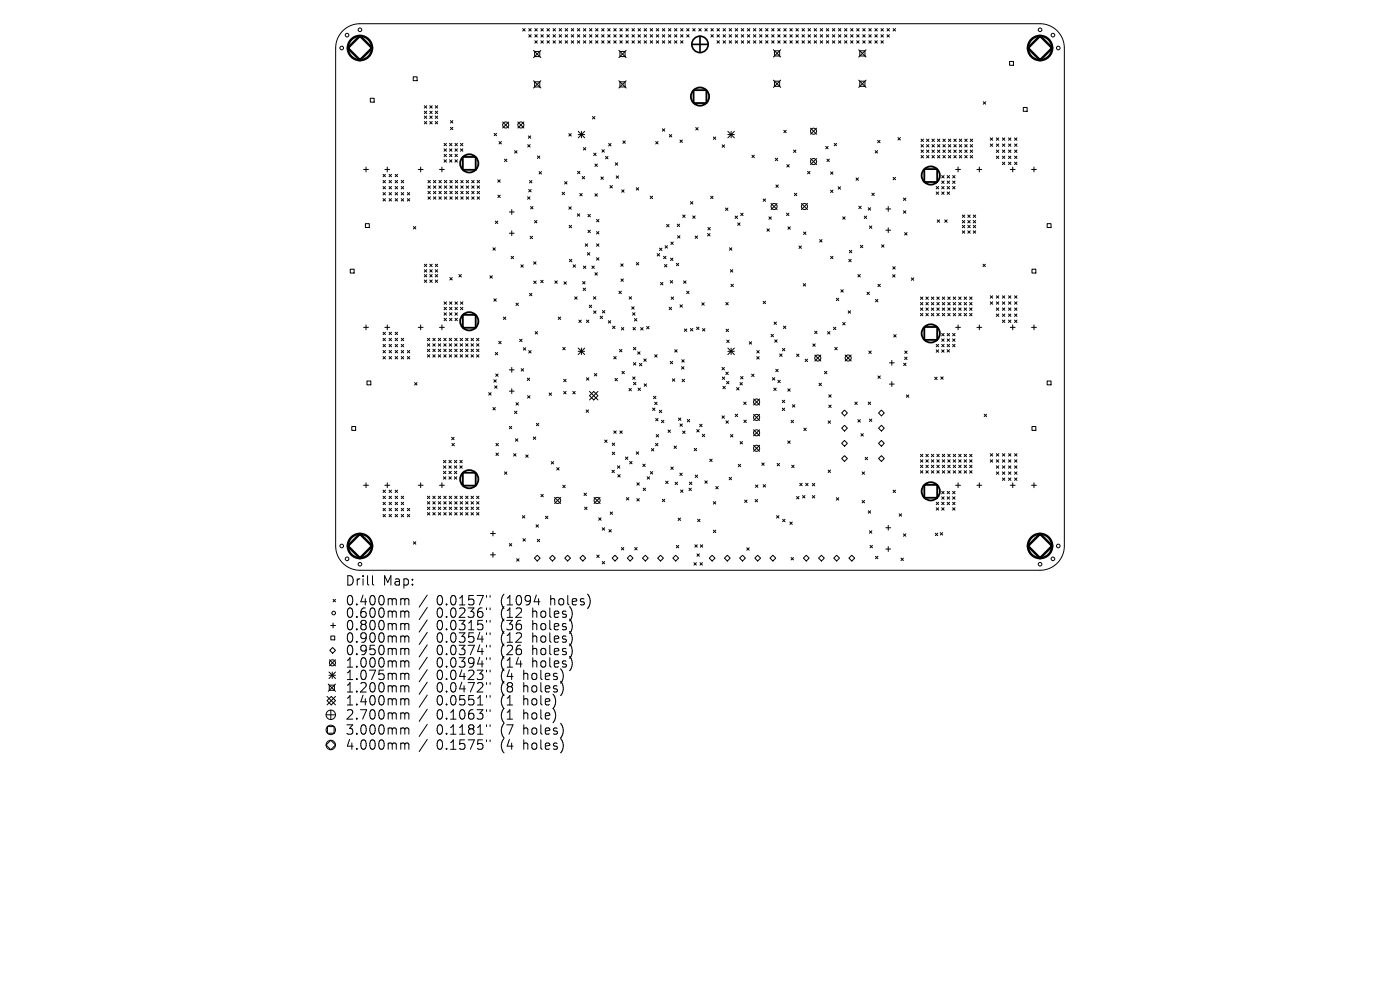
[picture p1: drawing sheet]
<svg xmlns="http://www.w3.org/2000/svg" width="297mm" height="210mm" viewBox="0 0 297 210" stroke-linecap="round" stroke-linejoin="round" font-family="sans-serif">
<defs><g id="words">
<g font-size="2.8">
<text x="73.2" y="124.5">Drill</text>
<text x="81.2" y="124.5">Map:</text>
<text x="73.2" y="128.7">0.400mm</text>
<text x="73.2" y="131.3">0.600mm</text>
<text x="92.6" y="128.7">0.0157&quot;</text>
<text x="92.6" y="131.3">0.0236&quot;</text>
<text x="106.3" y="128.7">(1094</text>
<text x="106.3" y="131.3">(12</text>
<text x="113.2" y="131.3">holes)</text>
<text x="117" y="128.7">holes)</text>
<text x="73.2" y="134">0.800mm</text>
<text x="73.2" y="136.6">0.900mm</text>
<text x="92.6" y="134">0.0315&quot;</text>
<text x="92.6" y="136.6">0.0354&quot;</text>
<text x="106.3" y="134">(36</text>
<text x="106.3" y="136.6">(12</text>
<text x="113.2" y="134">holes)</text>
<text x="113.2" y="136.6">holes)</text>
<text x="73.2" y="139.3">0.950mm</text>
<text x="73.2" y="141.9">1.000mm</text>
<text x="92.6" y="139.3">0.0374&quot;</text>
<text x="92.6" y="141.9">0.0394&quot;</text>
<text x="106.3" y="139.3">(26</text>
<text x="106.3" y="141.9">(14</text>
<text x="113.2" y="139.3">holes)</text>
<text x="113.2" y="141.9">holes)</text>
<text x="73.2" y="144.5">1.075mm</text>
<text x="73.2" y="147.2">1.200mm</text>
<text x="73.2" y="149.9">1.400mm</text>
<text x="92.6" y="144.5">0.0423&quot;</text>
<text x="92.6" y="147.2">0.0472&quot;</text>
<text x="92.6" y="149.9">0.0551&quot;</text>
<text x="106.3" y="144.5">(4</text>
<text x="106.3" y="147.2">(8</text>
<text x="106.3" y="149.9">(1</text>
<text x="111.3" y="144.5">holes)</text>
<text x="111.3" y="147.2">holes)</text>
<text x="111.3" y="149.9">hole)</text>
<text x="73.2" y="152.9">2.700mm</text>
<text x="92.6" y="152.9">0.1063&quot;</text>
<text x="106.3" y="152.9">(1</text>
<text x="111.3" y="152.9">hole)</text>
<text x="73.2" y="156.1">3.000mm</text>
<text x="73.2" y="159.3">4.000mm</text>
<text x="92.6" y="156.1">0.1181&quot;</text>
<text x="92.6" y="159.3">0.1575&quot;</text>
<text x="106.3" y="156.1">(7</text>
<text x="106.3" y="159.3">(4</text>
<text x="111.3" y="156.1">holes)</text>
<text x="111.3" y="159.3">holes)</text>
</g>
</g></defs>
<g fill="none" stroke="#000" stroke-width=".21">
<path d="M72.7 6.5a5.2 5.2 0 0 1 3.7-1.5h144.2a5.2 5.2 0 0 1 5.2 5.2v105.6a5.2 5.2 0 0 1-5.2 5.2h-144.2a5.2 5.2 0 0 1-5.2-5.2v-105.6a5.2 5.2 0 0 1 1.5-3.7zM87.7 16.3h.8v.8h-.8zM110.9 6.1l.5 .5M111.4 6.1l-.5 .5M112.2 7.4l.5 .5M112.2 6.1l.5 .5M112.7 7.4l-.5 .5M112.7 6.1l-.5 .5M113.2 17.1l1.5 1.6M113.2 10.7l1.5 1.5M113.4 10.9h1.1v1.1h-1.1zM113.4 17.4h1.1v1h-1.1z"/>
<path d="M113.5 8.6l.5 .6M113.5 6.1l.5 .5M113.5 7.4l.5 .5M114 6.1l-.5 .5M114 7.4l-.5 .5M114 8.6l-.5 .6M114.7 10.7l-1.5 1.5M114.7 17.1l-1.5 1.6M114.7 7.4l.6 .5M114.7 8.6l.6 .6M114.7 6.1l.6 .5M115.3 6.1l-.6 .5"/>
<path d="M115.3 7.4l-.6 .5M115.3 8.6l-.6 .6M116 8.6l.6 .6M116 7.4l.6 .5M116 6.1l.6 .5M116.6 6.1l-.6 .5M116.6 7.4l-.6 .5M116.6 8.6l-.6 .6M117.3 8.6l.5 .6M117.3 7.4l.5 .5M117.3 6.1l.5 .5M117.8 6.1l-.5 .5"/>
<path d="M117.8 7.4l-.5 .5M117.8 8.6l-.5 .6M118.6 8.6l.5 .6M118.6 7.4l.5 .5M118.6 6.1l.5 .5M119.1 6.1l-.5 .5M119.1 8.6l-.5 .6M119.1 7.4l-.5 .5M119.9 8.6l.5 .6M119.9 7.4l.5 .5M119.9 6.1l.5 .5M120.4 7.4l-.5 .5"/>
<path d="M120.4 8.6l-.5 .6M120.4 6.1l-.5 .5M121.2 8.6l.5 .6M121.2 7.4l.5 .5M121.2 6.1l.5 .5M121.7 6.1l-.5 .5M121.7 7.4l-.5 .5M121.7 8.6l-.5 .6M122.5 8.6l.5 .6M122.5 7.4l.5 .5M122.5 6.1l.5 .5M123 6.1l-.5 .5"/>
<path d="M123 7.4l-.5 .5M123 8.6l-.5 .6M123.8 7.4l.5 .5M123.8 6.1l.5 .5M123.8 8.6l.5 .6M124.3 6.1l-.5 .5M124.3 7.4l-.5 .5M124.3 8.6l-.5 .6M125.1 8.6l.5 .6M125.1 7.4l.5 .5M125.1 6.1l.5 .5M125.6 8.6l-.5 .6"/>
<path d="M125.6 6.1l-.5 .5M125.6 7.4l-.5 .5M126.3 8.6l.6 .6M126.3 7.4l.6 .5M126.3 6.1l.6 .5M126.9 7.4l-.6 .5M126.9 6.1l-.6 .5M126.9 8.6l-.6 .6M127.6 8.6l.5 .6M127.6 7.4l.5 .5M127.6 6.1l.5 .5M128.1 6.1l-.5 .5"/>
<path d="M128.1 7.4l-.5 .5M128.1 8.6l-.5 .6M128.9 8.6l.5 .6M128.9 7.4l.5 .5M128.9 6.1l.5 .5M129.4 6.1l-.5 .5M129.4 7.4l-.5 .5M129.4 8.6l-.5 .6M130.2 8.6l.5 .6M130.2 7.4l.5 .5M130.2 6.1l.5 .5M130.7 6.1l-.5 .5"/>
<path d="M130.7 7.4l-.5 .5M130.7 8.6l-.5 .6M131.3 10.7l1.5 1.5M131.3 17.1l1.5 1.6M131.5 8.6l.5 .6M131.5 7.4l.5 .5M131.5 6.1l.5 .5M131.5 10.9h1.1v1.1h-1.1zM131.5 17.4h1.1v1h-1.1zM132 6.1l-.5 .5M132 7.4l-.5 .5M132 8.6l-.5 .6"/>
<path d="M132.8 8.6l.5 .6M132.8 7.4l.5 .5M132.8 6.1l.5 .5M132.8 10.7l-1.5 1.5M132.8 17.1l-1.5 1.6M133.3 6.1l-.5 .5M133.3 7.4l-.5 .5M133.3 8.6l-.5 .6M134.1 8.6l.5 .6M134.1 7.4l.5 .5M134.1 6.1l.5 .5M134.6 6.1l-.5 .5"/>
<path d="M134.6 7.4l-.5 .5M134.6 8.6l-.5 .6M135.4 8.6l.5 .6M135.4 7.4l.5 .5M135.4 6.1l.5 .5M135.9 6.1l-.5 .5M135.9 7.4l-.5 .5M135.9 8.6l-.5 .6M136.6 8.6l.6 .6M136.6 7.4l.6 .5M136.6 6.1l.6 .5M137.2 6.1l-.6 .5"/>
<path d="M137.2 7.4l-.6 .5M137.2 8.6l-.6 .6M137.9 8.6l.6 .6M137.9 7.4l.6 .5M137.9 6.1l.6 .5M138.5 6.1l-.6 .5M138.5 7.4l-.6 .5M138.5 8.6l-.6 .6M139.2 8.6l.5 .6M139.2 6.1l.5 .5M139.2 7.4l.5 .5M139.7 6.1l-.5 .5"/>
<path d="M139.7 7.4l-.5 .5M139.7 8.6l-.5 .6M140.5 7.4l.5 .5M140.5 8.6l.5 .6M140.5 6.1l.5 .5M141 6.1l-.5 .5M141 7.4l-.5 .5M141 8.6l-.5 .6M141.8 8.6l.5 .6M141.8 7.4l.5 .5M141.8 6.1l.5 .5M142.3 6.1l-.5 .5"/>
<path d="M142.3 7.4l-.5 .5M142.3 8.6l-.5 .6M143.1 8.6l.5 .6M143.1 7.4l.5 .5M143.1 6.1l.5 .5M143.6 8.6l-.5 .6M143.6 6.1l-.5 .5M143.6 7.4l-.5 .5M144.4 8.6l.5 .6M144.4 7.4l.5 .5M144.4 6.1l.5 .5M144.9 7.4l-.5 .5"/>
<path d="M144.9 8.6l-.5 .6M144.9 6.1l-.5 .5M145.7 7.4l.5 .5M145.7 6.1l.5 .5M146.2 6.1l-.5 .5M146.2 7.4l-.5 .5M147 6.1l.5 .5M147.5 6.1l-.5 .5M148.2 6.1l.6 .5M148.8 6.1l-.6 .5M149.5 6.1l.5 .5M150 6.1l-.5 .5"/>
<path d="M150.8 7.4l.5 .5M150.8 6.1l.5 .5M151.3 6.1l-.5 .5M151.3 7.4l-.5 .5M152.1 8.6l.5 .6M152.1 7.4l.5 .5M152.1 6.1l.5 .5M152.6 6.1l-.5 .5M152.6 7.4l-.5 .5M152.6 8.6l-.5 .6M153.4 8.6l.5 .6M153.4 7.4l.5 .5"/>
<path d="M153.4 6.1l.5 .5M153.9 6.1l-.5 .5M153.9 7.4l-.5 .5M153.9 8.6l-.5 .6M154.7 8.6l.5 .6M154.7 7.4l.5 .5M154.7 6.1l.5 .5M155.2 6.1l-.5 .5M155.2 7.4l-.5 .5M155.2 8.6l-.5 .6M156 8.6l.5 .6M156 7.4l.5 .5"/>
<path d="M156 6.1l.5 .5M156.5 6.1l-.5 .5M156.5 7.4l-.5 .5M156.5 8.6l-.5 .6M157.3 8.6l.5 .6M157.3 7.4l.5 .5M157.3 6.1l.5 .5M157.8 8.6l-.5 .6M157.8 6.1l-.5 .5M157.8 7.4l-.5 .5M158.5 8.6l.6 .6M158.5 7.4l.6 .5"/>
<path d="M158.5 6.1l.6 .5M159.1 7.4l-.6 .5M159.1 6.1l-.6 .5M159.1 8.6l-.6 .6M159.8 8.6l.6 .6M159.8 7.4l.6 .5M159.8 6.1l.6 .5M160.4 6.1l-.6 .5M160.4 7.4l-.6 .5M160.4 8.6l-.6 .6M161.1 8.6l.5 .6M161.1 7.4l.5 .5"/>
<path d="M161.1 6.1l.5 .5M161.6 6.1l-.5 .5M161.6 7.4l-.5 .5M161.6 8.6l-.5 .6M162.4 8.6l.5 .6M162.4 7.4l.5 .5M162.4 6.1l.5 .5M162.9 6.1l-.5 .5M162.9 7.4l-.5 .5M162.9 8.6l-.5 .6M163.7 8.6l.5 .6M163.7 7.4l.5 .5"/>
<path d="M163.7 6.1l.5 .5M164.1 10.6l1.5 1.5M164.1 17l1.5 1.5M164.2 6.1l-.5 .5M164.2 7.4l-.5 .5M164.2 8.6l-.5 .6M164.3 10.8h1.1v1.1h-1.1zM164.3 17.2h1.1v1.1h-1.1zM165 8.6l.5 .6M165 7.4l.5 .5M165 6.1l.5 .5M165.5 6.1l-.5 .5"/>
<path d="M165.5 7.4l-.5 .5M165.5 8.6l-.5 .6M165.6 10.6l-1.5 1.5M165.6 17l-1.5 1.5M166.3 7.4l.5 .5M166.3 6.1l.5 .5M166.3 8.6l.5 .6M166.8 6.1l-.5 .5M166.8 7.4l-.5 .5M166.8 8.6l-.5 .6M167.6 8.6l.5 .6M167.6 7.4l.5 .5"/>
<path d="M167.6 6.1l.5 .5M168.1 6.1l-.5 .5M168.1 7.4l-.5 .5M168.1 8.6l-.5 .6M168.9 8.6l.5 .6M168.9 7.4l.5 .5M168.9 6.1l.5 .5M169.4 6.1l-.5 .5M169.4 7.4l-.5 .5M169.4 8.6l-.5 .6M170.1 8.6l.6 .6M170.1 7.4l.6 .5"/>
<path d="M170.1 6.1l.6 .5M170.7 6.1l-.6 .5M170.7 7.4l-.6 .5M170.7 8.6l-.6 .6M171.4 8.6l.5 .6M171.4 7.4l.5 .5M171.4 6.1l.5 .5M171.9 6.1l-.5 .5M171.9 7.4l-.5 .5M171.9 8.6l-.5 .6M172.7 8.6l.5 .6M172.7 7.4l.5 .5"/>
<path d="M172.7 6.1l.5 .5M173.2 6.1l-.5 .5M173.2 7.4l-.5 .5M173.2 8.6l-.5 .6M174 8.6l.5 .6M174 7.4l.5 .5M174 6.1l.5 .5M174.5 6.1l-.5 .5M174.5 7.4l-.5 .5M174.5 8.6l-.5 .6M175.3 8.6l.5 .6M175.3 7.4l.5 .5"/>
<path d="M175.3 6.1l.5 .5M175.8 8.6l-.5 .6M175.8 6.1l-.5 .5M175.8 7.4l-.5 .5M176.6 8.6l.5 .6M176.6 7.4l.5 .5M176.6 6.1l.5 .5M177.1 7.4l-.5 .5M177.1 6.1l-.5 .5M177.1 8.6l-.5 .6M177.9 8.6l.5 .6M177.9 7.4l.5 .5"/>
<path d="M177.9 6.1l.5 .5M178.4 8.6l-.5 .6M178.4 6.1l-.5 .5M178.4 7.4l-.5 .5M179.2 8.6l.5 .6M179.2 7.4l.5 .5M179.2 6.1l.5 .5M179.7 8.6l-.5 .6M179.7 7.4l-.5 .5M179.7 6.1l-.5 .5M180.4 8.6l.6 .6M180.4 7.4l.6 .5"/>
<path d="M180.4 6.1l.6 .5M181 7.4l-.6 .5M181 8.6l-.6 .6M181 6.1l-.6 .5M181.7 8.6l.6 .6M181.7 6.1l.6 .5M181.7 7.4l.6 .5M182.2 10.6l1.5 1.5M182.2 17l1.5 1.5M182.3 6.1l-.6 .5M182.3 7.4l-.6 .5M182.3 8.6l-.6 .6"/>
<path d="M182.4 10.8h1.1v1.1h-1.1zM182.4 17.2h1.1v1.1h-1.1zM183 7.4l.5 .5M183 8.6l.5 .6M183 6.1l.5 .5M183.5 6.1l-.5 .5M183.5 8.6l-.5 .6M183.5 7.4l-.5 .5M183.7 10.6l-1.5 1.5M183.7 17l-1.5 1.5M184.3 8.6l.5 .6M184.3 7.4l.5 .5"/>
<path d="M184.3 6.1l.5 .5M184.8 7.4l-.5 .5M184.8 6.1l-.5 .5M184.8 8.6l-.5 .6M185.6 8.6l.5 .6M185.6 7.4l.5 .5M185.6 6.1l.5 .5M186.1 8.6l-.5 .6M186.1 6.1l-.5 .5M186.1 7.4l-.5 .5M186.9 8.6l.5 .6M186.9 7.4l.5 .5"/>
<path d="M186.9 6.1l.5 .5M187.4 7.4l-.5 .5M187.4 8.6l-.5 .6M187.4 6.1l-.5 .5M188.2 7.4l.5 .5M188.2 6.1l.5 .5M188.7 6.1l-.5 .5M188.7 7.4l-.5 .5M189.5 6.1l.5 .5M190 6.1l-.5 .5M214.2 13h.8v.9h-.8zM77.1 35.9h1.1"/>
<path d="M77.6 35.4v1.1M78.6 20.8h.8v.9h-.8zM81.3 37l.5 .5M81.3 38.3l.5 .5M81.3 39.6l.5 .5M81.6 35.9h1.1M81.8 37l-.5 .5M81.8 38.3l-.5 .5M81.8 39.6l-.5 .5M82.2 35.4v1.1M82.5 38.3l.6 .5M82.5 39.6l.6 .5"/>
<path d="M82.5 37l.6 .5M83.1 37l-.6 .5M83.1 38.3l-.6 .5M83.1 39.6l-.6 .5M83.8 39.6l.5 .5M83.8 38.3l.5 .5M83.8 37l.5 .5M84.3 37l-.5 .5M84.3 38.3l-.5 .5M84.3 39.6l-.5 .5M85.1 39.6l.5 .5M85.1 38.3l.5 .5"/>
<path d="M85.6 38.3l-.5 .5M85.6 39.6l-.5 .5M88.7 35.9h1.1M89.2 35.4v1.1M90 22.4l.5 .5M90 23.6l.5 .5M90 24.6l.5 .5M90 25.8l.5 .5M90.5 22.4l-.5 .5M90.5 23.6l-.5 .5M90.5 24.6l-.5 .5M90.5 25.8l-.5 .5"/>
<path d="M90.8 38.3l.5 .5M90.8 39.4l.5 .5M91.2 23.6l.5 .5M91.2 25.8l.5 .5M91.2 22.4l.5 .5M91.2 24.6l.5 .5M91.3 38.3l-.5 .5M91.3 39.4l-.5 .5M91.7 22.4l-.5 .5M91.7 24.6l-.5 .5M91.7 23.6l-.5 .5M91.7 25.8l-.5 .5"/>
<path d="M91.9 39.4l.6 .5M91.9 38.3l.6 .5M92.3 25.8l.5 .5M92.3 22.4l.5 .5M92.3 23.6l.5 .5M92.3 24.6l.5 .5M92.5 38.3l-.6 .5M92.5 39.4l-.6 .5M92.8 22.4l-.5 .5M92.8 24.6l-.5 .5M92.8 23.6l-.5 .5M92.8 25.8l-.5 .5"/>
<path d="M93.1 39.4l.5 .5M93.1 38.3l.5 .5M93.2 35.9h1.1M93.6 38.3l-.5 .5M93.6 39.4l-.5 .5M93.8 35.4v1.1M94.2 30.4l.5 .5M94.2 31.6l.5 .5M94.2 32.7l.5 .5M94.2 33.9l.5 .5M94.3 39.4l.5 .5M94.3 38.3l.5 .5"/>
<path d="M94.7 30.4l-.5 .5M94.7 31.6l-.5 .5M94.7 32.7l-.5 .5M94.7 33.9l-.5 .5M94.8 38.3l-.5 .5M94.8 39.4l-.5 .5M95.4 31.6l.5 .5M95.4 32.7l.5 .5M95.4 33.9l.5 .5M95.4 30.4l.5 .5M95.4 39.4l.5 .5M95.4 38.3l.5 .5"/>
<path d="M95.6 25.6l.5 .5M95.6 27l.5 .5M95.9 30.4l-.5 .5M95.9 31.6l-.5 .5M95.9 32.7l-.5 .5M95.9 33.9l-.5 .5M95.9 39.4l-.5 .5M95.9 38.3l-.5 .5M96.1 25.6l-.5 .5M96.1 27l-.5 .5M96.5 32.7l.5 .5M96.5 33.9l.5 .5"/>
<path d="M96.5 31.6l.5 .5M96.5 30.4l.5 .5M96.6 39.4l.5 .5M96.6 38.3l.5 .5M97 30.4l-.5 .5M97 31.6l-.5 .5M97 32.7l-.5 .5M97 33.9l-.5 .5M97.1 38.3l-.5 .5M97.1 39.4l-.5 .5M97.7 31.6l.5 .5M97.7 30.4l.5 .5"/>
<path d="M97.7 39.4l.6 .5M97.7 38.3l.6 .5M98.2 30.4l-.5 .5M98.2 31.6l-.5 .5M98.3 38.3l-.6 .5M98.3 39.4l-.6 .5M98.9 39.4l.5 .5M98.9 38.3l.5 .5M99.4 38.3l-.5 .5M99.4 39.4l-.5 .5M100.1 39.4l.5 .5M100.1 38.3l.5 .5"/>
<path d="M100.6 38.3l-.5 .5M100.6 39.4l-.5 .5M101.2 39.4l.5 .5M101.2 38.3l.5 .5M101.7 38.3l-.5 .5M101.7 39.4l-.5 .5M104.8 28.3l.5 .5M105.3 28.3l-.5 .5M105.6 38.1l.5 .6M105.9 30l.5 .5M106.1 38.1l-.5 .6M106.4 30l-.5 .5"/>
<path d="M106.6 25.9l1.3 1.3M107 33.8l.5 .5M107.5 33.8l-.5 .5M107.9 25.9l-1.3 1.3M109.2 32l.5 .5M109.7 32l-.5 .5M109.9 25.9l1.2 1.3M111.1 25.9l-1.2 1.3M111.9 30.7l.6 .5M112.1 28.8l.5 .5M112.3 38.3l.5 .5M112.5 30.7l-.6 .5"/>
<path d="M112.6 28.8l-.5 .5M112.8 38.3l-.5 .5M114 33.1l.5 .5M114.4 36.4l.5 .5M114.5 33.1l-.5 .5M114.9 36.4l-.5 .5M119.8 38.5l.5 .5M120.3 38.5l-.5 .5M120.7 28.3l.5 .6M121.2 28.3l-.5 .6M122.5 36.3l.5 .6M122.7 27.9l1.3 1.3"/>
<path d="M122.7 28.5h1.3M123 36.3l-.5 .6M123.3 27.9v1.3M123.5 37.4l.5 .5M123.8 31.3l.5 .5M124 37.4l-.5 .5M124 27.9l-1.3 1.3M124.3 31.3l-.5 .5M125.7 24.7l.5 .5M125.9 32.5l.6 .5M126.2 24.7l-.5 .5M126.2 34.8l.5 .5"/>
<path d="M126.5 32.5l-.6 .5M126.7 34.8l-.5 .5M127.5 37.5l.5 .6M127.7 31.8l.5 .5M128 37.5l-.5 .6M128.2 31.8l-.5 .5M128.5 33.2l.5 .5M129 33.2l-.5 .5M129.1 30.4l.5 .6M129.4 39.4l.5 .5M129.6 30.4l-.5 .6M129.9 39.4l-.5 .5"/>
<path d="M130.5 34.5l.5 .5M130.7 37.3l.5 .5M131 34.5l-.5 .5M131.2 37.3l-.5 .5M132.1 29.9l.6 .5M132.7 29.9l-.6 .5M135 39.8l.5 .5M135.5 39.8l-.5 .5M139.1 30l.5 .5M139.6 30l-.5 .5M140.5 27.3l.5 .5M141 27.3l-.5 .5"/>
<path d="M142 28.5l.5 .6M142.5 28.5l-.5 .6M144.2 29.7l.6 .5M144.8 29.7l-.6 .5M147.6 27.1l.5 .5M148.1 27.1l-.5 .5M151.3 29.1l.6 .5M151.9 29.1l-.6 .5M153.2 30.7l.5 .5M153.7 30.7l-.5 .5M154.4 27.9l1.4 1.3M154.4 28.5h1.4"/>
<path d="M155.1 27.9v1.3M155.8 27.9l-1.4 1.3M159.5 32.9l.5 .5M160 32.9l-.5 .5M164.5 33.6l.5 .5M164.6 39.2l.5 .5M165 33.6l-.5 .5M165.1 39.2l-.5 .5M166.3 27.6l.5 .6M166.8 27.6l-.5 .6M166.9 34.9l.5 .5M167.4 34.9l-.5 .5"/>
<path d="M168.3 31.8l.6 .5M168.9 31.8l-.6 .5M171.3 36.4l.5 .5M171.8 36.4l-.5 .5M171.9 27.2l1.3 1.3M171.9 33.6l1.3 1.3M173.2 33.6l-1.3 1.3M173.2 27.2l-1.3 1.3M175.2 31.1l.5 .5M175.4 33.8l.5 .5M175.7 31.1l-.5 .5M175.9 33.8l-.5 .5"/>
<path d="M176.2 36.5l.5 .5M176.7 36.5l-.5 .5M177 30.4l.5 .5M177.5 30.4l-.5 .5M177.8 39.6l.5 .5M178.3 39.6l-.5 .5M181.6 37.7l.5 .6M182.1 37.7l-.5 .6M185.7 32l.5 .5M186.2 32l-.5 .5M186.2 29.8l.5 .5M186.7 29.8l-.5 .5"/>
<path d="M189.5 37.6l.5 .5M190 37.6l-.5 .5M190.5 29.2l.5 .5M191 29.2l-.5 .5M195.4 29.5l.5 .5M195.4 30.7l.5 .5M195.4 31.8l.5 .5M195.4 33l.5 .5M195.9 33l-.5 .5M195.9 29.5l-.5 .5M195.9 30.7l-.5 .5M195.9 31.8l-.5 .5"/>
<path d="M196.6 30.7l.5 .5M196.6 31.8l.5 .5M196.6 33l.5 .5M196.6 29.5l.5 .5M197.1 31.8l-.5 .5M197.1 33l-.5 .5M197.1 29.5l-.5 .5M197.1 30.7l-.5 .5M197.7 31.8l.5 .5M197.7 33l.5 .5M197.7 30.7l.5 .5M197.7 29.5l.5 .5"/>
<path d="M198.2 30.7l-.5 .5M198.2 31.8l-.5 .5M198.2 29.5l-.5 .5M198.2 33l-.5 .5M198.6 39.6l.5 .5M198.9 33l.5 .5M198.9 31.8l.5 .5M198.9 30.7l.5 .5M198.9 29.5l.5 .5M199.1 39.6l-.5 .5M199.4 29.5l-.5 .5M199.4 30.7l-.5 .5"/>
<path d="M199.4 31.8l-.5 .5M199.4 33l-.5 .5M199.8 38.4l.5 .5M199.8 37.2l.5 .6M199.8 39.6l.5 .5M200 33l.5 .5M200 31.8l.5 .5M200 30.7l.5 .5M200 29.5l.5 .5M200.3 37.2l-.5 .6M200.3 38.4l-.5 .5M200.3 39.6l-.5 .5"/>
<path d="M200.5 29.5l-.5 .5M200.5 30.7l-.5 .5M200.5 31.8l-.5 .5M200.5 33l-.5 .5M200.9 39.6l.5 .5M200.9 38.4l.5 .5M200.9 37.2l.5 .6M201.2 33l.5 .5M201.2 31.8l.5 .5M201.2 30.7l.5 .5M201.2 29.5l.5 .5M201.4 37.2l-.5 .6"/>
<path d="M201.4 38.4l-.5 .5M201.4 39.6l-.5 .5M201.7 33l-.5 .5M201.7 29.5l-.5 .5M201.7 30.7l-.5 .5M201.7 31.8l-.5 .5M202.1 38.4l.5 .5M202.1 37.2l.5 .6M202.1 39.6l.5 .5M202.3 33l.6 .5M202.3 31.8l.6 .5M202.3 30.7l.6 .5"/>
<path d="M202.3 29.5l.6 .5M202.6 37.2l-.5 .6M202.6 38.4l-.5 .5M202.6 39.6l-.5 .5M202.7 35.9h1.1M202.9 31.8l-.6 .5M202.9 33l-.6 .5M202.9 29.5l-.6 .5M202.9 30.7l-.6 .5M203.3 35.4v1.1M203.5 33l.5 .5M203.5 31.8l.5 .5"/>
<path d="M203.5 30.7l.5 .5M203.5 29.5l.5 .5M204 30.7l-.5 .5M204 31.8l-.5 .5M204 29.5l-.5 .5M204 33l-.5 .5M204.7 33l.5 .5M204.7 31.8l.5 .5M204.7 29.5l.5 .5M204.7 30.7l.5 .5M205.2 29.5l-.5 .5M205.2 30.7l-.5 .5"/>
<path d="M205.2 31.8l-.5 .5M205.2 33l-.5 .5M205.8 33l.5 .5M205.8 30.7l.5 .5M205.8 31.8l.5 .5M205.8 29.5l.5 .5M206.3 33l-.5 .5M206.3 29.5l-.5 .5M206.3 30.7l-.5 .5M206.3 31.8l-.5 .5M207.2 35.9h1.1M207.8 35.4v1.1"/>
<path d="M208.6 21.6l.5 .5M209.1 21.6l-.5 .5M210.1 29.3l.5 .5M210.1 30.5l.5 .6M210.6 29.3l-.5 .5M210.6 30.5l-.5 .6M211.4 29.3l.5 .5M211.4 30.5l.5 .6M211.4 31.8l.5 .5M211.4 33.1l.5 .5M211.9 29.3l-.5 .5M211.9 30.5l-.5 .6"/>
<path d="M211.9 31.8l-.5 .5M211.9 33.1l-.5 .5M212.7 30.5l.5 .6M212.7 31.8l.5 .5M212.7 33.1l.5 .5M212.7 34.4l.5 .5M212.7 29.3l.5 .5M213.2 34.4l-.5 .5M213.2 29.3l-.5 .5M213.2 30.5l-.5 .6M213.2 31.8l-.5 .5M213.2 33.1l-.5 .5"/>
<path d="M213.9 33.1l.6 .5M213.9 34.4l.6 .5M213.9 30.5l.6 .6M213.9 29.3l.6 .5M213.9 31.8l.6 .5M214.3 35.9h1.1M214.5 34.4l-.6 .5M214.5 33.1l-.6 .5M214.5 29.3l-.6 .5M214.5 30.5l-.6 .6M214.5 31.8l-.6 .5M214.8 35.4v1.1"/>
<path d="M215.2 34.4l.5 .5M215.2 31.8l.5 .5M215.2 30.5l.5 .6M215.2 33.1l.5 .5M215.2 29.3l.5 .5M215.7 33.1l-.5 .5M215.7 34.4l-.5 .5M215.7 31.8l-.5 .5M215.7 29.3l-.5 .5M215.7 30.5l-.5 .6M217.1 22.8h.8v.8h-.8zM218.8 35.9h1.1"/>
<path d="M219.4 35.4v1.1M74.3 57.1h.8v.8h-.8zM77.5 47.4h.8v.9h-.8zM81.3 40.8l.5 .6M81.3 42.1l.5 .5M81.8 40.8l-.5 .6M81.8 42.1l-.5 .5M82.5 40.8l.6 .6M82.5 42.1l.6 .5M83.1 40.8l-.6 .6M83.1 42.1l-.6 .5M83.8 40.8l.5 .6"/>
<path d="M83.8 42.1l.5 .5M84.3 40.8l-.5 .6M84.3 42.1l-.5 .5M85.1 40.8l.5 .6M85.1 42.1l.5 .5M85.6 40.8l-.5 .6M85.6 42.1l-.5 .5M86.4 42.1l.5 .5M86.4 40.8l.5 .6M86.9 40.8l-.5 .6M86.9 42.1l-.5 .5M87.7 48.1l.5 .5"/>
<path d="M88.2 48.1l-.5 .5M90 56l.5 .6M90 57.2l.5 .5M90 58.2l.5 .6M90 59.4l.5 .5M90.5 56l-.5 .6M90.5 57.2l-.5 .5M90.5 58.2l-.5 .6M90.5 59.4l-.5 .5M90.8 40.6l.5 .5M90.8 41.7l.5 .6M91.2 57.2l.5 .5"/>
<path d="M91.2 59.4l.5 .5M91.2 56l.5 .6M91.2 58.2l.5 .6M91.3 40.6l-.5 .5M91.3 41.7l-.5 .6M91.7 56l-.5 .6M91.7 58.2l-.5 .6M91.7 57.2l-.5 .5M91.7 59.4l-.5 .5M91.9 40.6l.6 .5M91.9 41.7l.6 .6M92.3 57.2l.5 .5"/>
<path d="M92.3 59.4l.5 .5M92.3 56l.5 .6M92.3 58.2l.5 .6M92.5 40.6l-.6 .5M92.5 41.7l-.6 .6M92.8 59.4l-.5 .5M92.8 56l-.5 .6M92.8 58.2l-.5 .6M92.8 57.2l-.5 .5M93.1 40.6l.5 .5M93.1 41.7l.5 .6M93.6 40.6l-.5 .5"/>
<path d="M93.6 41.7l-.5 .6M94.3 41.7l.5 .6M94.3 40.6l.5 .5M94.8 40.6l-.5 .5M94.8 41.7l-.5 .6M95.4 41.7l.5 .6M95.4 40.6l.5 .5M95.4 58.9l.5 .5M95.9 58.9l-.5 .5M95.9 40.6l-.5 .5M95.9 41.7l-.5 .6M96.6 41.7l.5 .6"/>
<path d="M96.6 40.6l.5 .5M97.1 40.6l-.5 .5M97.1 41.7l-.5 .6M97.4 58.2l.5 .6M97.7 41.7l.6 .6M97.7 40.6l.6 .5M97.9 58.2l-.5 .6M98.3 40.6l-.6 .5M98.3 41.7l-.6 .6M98.9 40.6l.5 .5M98.9 41.7l.5 .6M99.4 40.6l-.5 .5"/>
<path d="M99.4 41.7l-.5 .6M100.1 41.7l.5 .6M100.1 40.6l.5 .5M100.6 40.6l-.5 .5M100.6 41.7l-.5 .6M101.2 41.7l.5 .6M101.2 40.6l.5 .5M101.7 40.6l-.5 .5M101.7 41.7l-.5 .6M103.9 58.5l.5 .5M104.4 58.5l-.5 .5M104.6 52.6l.5 .5"/>
<path d="M105.1 52.6l-.5 .5M105.1 46.9l.5 .5M105.6 46.9l-.5 .5M105.6 41.4l.5 .5M106.1 41.4l-.5 .5M108.1 45h1M108.1 49.5h1M108.4 54.4l.6 .5M108.6 44.5v1M108.6 49v1M109 54.4l-.6 .5M110.5 56.2l.5 .5"/>
<path d="M111 56.2l-.5 .5M111.9 41.7l.5 .6M112.2 40.2l.5 .5M112.4 41.7l-.5 .6M112.5 50.1l.5 .5M112.6 43.8l.5 .5M112.7 40.2l-.5 .5M113 50.1l-.5 .5M113.1 43.8l-.5 .5M113.2 55.5l.5 .5M113.2 59.6l.5 .5M113.4 46.8l.5 .5"/>
<path d="M113.7 55.5l-.5 .5M113.7 59.6l-.5 .5M113.9 46.8l-.5 .5M114.7 59.5l.5 .5M115.2 59.5l-.5 .5M117.7 59.6l.5 .5M118.2 59.6l-.5 .5M119.3 40.8l.5 .5M119.6 59.8l.6 .5M119.8 40.8l-.5 .5M120.2 59.8l-.6 .5M120.7 43.9l.5 .5"/>
<path d="M120.7 47.8l.6 .5M120.8 55l.5 .5M121.2 43.9l-.5 .5M121.3 47.8l-.6 .5M121.3 55l-.5 .5M121.6 56.2l.5 .5M122.1 56.2l-.5 .5M122.5 45.4l.5 .5M123 45.4l-.5 .5M123 41l.5 .6M123.5 41l-.5 .6M123.6 59.7l.5 .5"/>
<path d="M123.8 56.4l.5 .5M124.1 59.7l-.5 .5M124.2 51.7l.5 .5M124.3 56.4l-.5 .5M124.6 53.6l.5 .5M124.7 51.7l-.5 .5M124.7 48.8l.5 .5M124.7 45.5l.5 .5M125.1 53.6l-.5 .5M125.2 45.5l-.5 .5M125.2 48.8l-.5 .5M125.6 56.4l.5 .5"/>
<path d="M126.1 56.4l-.5 .5M126.2 41.1l.5 .5M126.2 57.8l.5 .6M126.5 46.6l.6 .5M126.5 49.1l.6 .5M126.5 51.7l.6 .5M126.5 54.7l.6 .5M126.7 41.1l-.5 .5M126.7 57.8l-.5 .6M127.1 46.6l-.6 .5M127.1 49.1l-.6 .5M127.1 51.7l-.6 .5"/>
<path d="M127.1 54.7l-.6 .5M131.7 56l.5 .5M131.7 59.2l.5 .5M131.9 40.3l.5 .5M132.2 56l-.5 .5M132.2 59.2l-.5 .5M132.4 40.3l-.5 .5M135 55.7l.5 .5M135.5 55.7l-.5 .5M137.9 41.6l.6 .5M138.5 41.6l-.6 .5M139.4 53.8l.5 .5"/>
<path d="M139.9 52.6l.5 .6M139.9 53.8l-.5 .5M140.1 59.9l.5 .5M140.4 52.6l-.5 .6M140.6 59.9l-.5 .5M140.8 54.4l.5 .5M141 56.1l.5 .5M141.1 52.1l.5 .5M141.3 54.4l-.5 .5M141.4 47.6l.5 .5M141.5 56.1l-.5 .5M141.6 52.1l-.5 .5"/>
<path d="M141.9 47.6l-.5 .5M142.2 59.5l.5 .5M142.3 54.8l.5 .5M142.3 51.3l.5 .6M142.7 59.5l-.5 .5M142.8 54.8l-.5 .5M142.8 51.3l-.5 .6M143.5 55.9l.5 .5M143.7 47.5l.5 .6M143.7 50l.5 .5M144 55.9l-.5 .5M144.2 47.5l-.5 .6"/>
<path d="M144.2 50l-.5 .5M144.8 45.6l.5 .5M145 59.6l.5 .5M145.3 45.6l-.5 .5M145.5 59.6l-.5 .5M146.5 42.8l.5 .5M147 45.8l.5 .5M147 42.8l-.5 .5M147.5 50.1l.5 .5M147.5 45.8l-.5 .5M148 50.1l-.5 .5M150.1 49.5l.5 .6"/>
<path d="M150.2 48.3l.5 .5M150.6 49.5l-.5 .6M150.7 48.3l-.5 .5M150.8 41.6l.5 .5M151.3 41.6l-.5 .5M153.9 44.1l.5 .5M154.4 44.1l-.5 .5M154.7 52.6l.6 .5M154.9 57.2l.6 .5M155.3 52.6l-.6 .5M155.5 57.2l-.6 .5M155.9 45.8l.6 .5"/>
<path d="M156.5 45.8l-.6 .5M156.5 47.3l.5 .5M157 47.3l-.5 .5M157.1 45.2l.5 .5M157.6 45.2l-.5 .5M161.9 42.2l.5 .5M162.4 42.2l-.5 .5M162.7 48.5l.5 .6M163.1 46l.5 .5M163.2 48.5l-.5 .6M163.6 43.2l1.3 1.3M163.6 46l-.5 .5"/>
<path d="M164.9 43.2l-1.3 1.3M166.9 45.2l.5 .5M167.1 48.1l.6 .5M167.4 45.2l-.5 .5M167.7 48.1l-.6 .5M168.5 41l.5 .5M169 41l-.5 .5M169.5 52.2l.5 .5M170 43.2l1.3 1.3M170 52.2l-.5 .5M170.5 49.2l.5 .5M171 49.2l-.5 .5"/>
<path d="M171.3 43.2l-1.3 1.3M173.9 50.8l.5 .5M174.4 50.8l-.5 .5M176.2 40.3l.5 .5M176.2 54.4l.5 .5M176.7 54.4l-.5 .5M176.7 40.3l-.5 .5M178.8 46l.5 .5M179.3 46l-.5 .5M180.1 55l.5 .5M180.2 53.1l.5 .5M180.6 55l-.5 .5"/>
<path d="M180.7 53.1l-.5 .5M182 58.2l.5 .6M182.2 43.7l.5 .6M182.5 58.2l-.5 .6M182.5 52l.5 .6M182.7 43.7l-.5 .6M183 52l-.5 .6M183.3 45.8l.6 .6M183.9 45.8l-.6 .6M184.2 44.1l.5 .5M184.4 47.9l.6 .5M184.7 44.1l-.5 .5"/>
<path d="M185 47.9l-.6 .5M185 41l.5 .5M185.5 41l-.5 .5M187 51.9l.5 .5M187.5 51.9l-.5 .5M187.9 44.3h1.1M187.9 48.8h1.1M188.4 43.8v1M188.4 48.3v1M189.4 58.3l.5 .5M189.4 56.6l.5 .5M189.9 58.3l-.5 .5"/>
<path d="M189.9 56.6l-.5 .5M191.7 42l.5 .5M191.7 44.7l.5 .5M191.9 49.3l.5 .6M192.2 44.7l-.5 .5M192.2 42l-.5 .5M192.4 49.3l-.5 .6M193.3 58.9l.5 .6M193.8 58.9l-.5 .6M198.6 40.7l.5 .5M198.8 46.6l.5 .6M199.1 40.7l-.5 .5"/>
<path d="M199.3 46.6l-.5 .6M199.8 40.7l.5 .5M200.3 40.7l-.5 .5M200.4 46.6l.5 .6M200.9 40.7l.5 .5M200.9 46.6l-.5 .6M201.4 40.7l-.5 .5M204.2 49l.5 .5M204.2 45.6l.5 .5M204.2 46.8l.5 .5M204.2 47.8l.5 .5M204.7 45.6l-.5 .5"/>
<path d="M204.7 46.8l-.5 .5M204.7 47.8l-.5 .5M204.7 49l-.5 .5M205.3 46.8l.5 .5M205.3 49l.5 .5M205.3 45.6l.5 .5M205.3 47.8l.5 .5M205.8 45.6l-.5 .5M205.8 47.8l-.5 .5M205.8 46.8l-.5 .5M205.8 49l-.5 .5M206.5 49l.5 .5"/>
<path d="M206.5 45.6l.5 .5M206.5 46.8l.5 .5M206.5 47.8l.5 .5M207 45.6l-.5 .5M207 47.8l-.5 .5M207 46.8l-.5 .5M207 49l-.5 .5M208.5 56l.5 .6M209 56l-.5 .6M218.9 57.1h.8v.8h-.8zM222.1 47.4h.9v.9h-.9zM77.1 69.4h1.1"/>
<path d="M77.6 68.9v1.1M81.3 70.5l.5 .5M81.3 71.8l.5 .5M81.3 73.1l.5 .5M81.3 74.3l.5 .6M81.3 75.6l.5 .5M81.6 69.4h1.1M81.8 70.5l-.5 .5M81.8 71.8l-.5 .5M81.8 73.1l-.5 .5M81.8 74.3l-.5 .6M81.8 75.6l-.5 .5"/>
<path d="M82.2 68.9v1.1M82.5 71.8l.6 .5M82.5 73.1l.6 .5M82.5 75.6l.6 .5M82.5 70.5l.6 .5M82.5 74.3l.6 .6M83.1 70.5l-.6 .5M83.1 71.8l-.6 .5M83.1 73.1l-.6 .5M83.1 74.3l-.6 .6M83.1 75.6l-.6 .5M83.8 73.1l.5 .5"/>
<path d="M83.8 74.3l.5 .6M83.8 71.8l.5 .5M83.8 75.6l.5 .5M83.8 70.5l.5 .5M84.3 70.5l-.5 .5M84.3 71.8l-.5 .5M84.3 73.1l-.5 .5M84.3 74.3l-.5 .6M84.3 75.6l-.5 .5M85.1 74.3l.5 .6M85.1 75.6l.5 .5M85.1 73.1l.5 .5"/>
<path d="M85.1 71.8l.5 .5M85.6 71.8l-.5 .5M85.6 73.1l-.5 .5M85.6 74.3l-.5 .6M85.6 75.6l-.5 .5M86.4 75.6l.5 .5M86.4 74.3l.5 .6M86.9 74.3l-.5 .6M86.9 75.6l-.5 .5M88.7 69.4h1.1M89.2 68.9v1.1M90.7 71.8l.5 .5"/>
<path d="M90.7 72.9l.5 .5M90.7 74.1l.5 .5M90.7 75.2l.5 .6M91.2 71.8l-.5 .5M91.2 72.9l-.5 .5M91.2 74.1l-.5 .5M91.2 75.2l-.5 .6M91.8 72.9l.5 .5M91.8 74.1l.5 .5M91.8 75.2l.5 .6M91.8 71.8l.5 .5M92.3 71.8l-.5 .5"/>
<path d="M92.3 72.9l-.5 .5M92.3 74.1l-.5 .5M92.3 75.2l-.5 .6M93 74.1l.5 .5M93 75.2l.5 .6M93 72.9l.5 .5M93 71.8l.5 .5M93.2 69.4h1.1M93.5 71.8l-.5 .5M93.5 72.9l-.5 .5M93.5 74.1l-.5 .5M93.5 75.2l-.5 .6"/>
<path d="M93.8 68.9v1.1M94.1 75.2l.6 .6M94.1 74.1l.6 .5M94.1 72.9l.6 .5M94.1 71.8l.6 .5M94.2 64l.5 .5M94.2 65.2l.5 .5M94.2 66.4l.5 .5M94.2 67.5l.5 .5M94.7 71.8l-.6 .5M94.7 72.9l-.6 .5M94.7 74.1l-.6 .5"/>
<path d="M94.7 75.2l-.6 .6M94.7 64l-.5 .5M94.7 65.2l-.5 .5M94.7 66.4l-.5 .5M94.7 67.5l-.5 .5M95.3 75.2l.5 .6M95.3 74.1l.5 .5M95.3 72.9l.5 .5M95.3 71.8l.5 .5M95.4 65.2l.5 .5M95.4 66.4l.5 .5M95.4 67.5l.5 .5"/>
<path d="M95.4 64l.5 .5M95.8 71.8l-.5 .5M95.8 72.9l-.5 .5M95.8 74.1l-.5 .5M95.8 75.2l-.5 .6M95.9 64l-.5 .5M95.9 65.2l-.5 .5M95.9 66.4l-.5 .5M95.9 67.5l-.5 .5M96.5 75.2l.5 .6M96.5 74.1l.5 .5M96.5 72.9l.5 .5"/>
<path d="M96.5 71.8l.5 .5M96.5 66.4l.5 .5M96.5 67.5l.5 .5M96.5 65.2l.5 .5M96.5 64l.5 .5M97 71.8l-.5 .5M97 72.9l-.5 .5M97 74.1l-.5 .5M97 75.2l-.5 .6M97 64l-.5 .5M97 65.2l-.5 .5M97 66.4l-.5 .5"/>
<path d="M97 67.5l-.5 .5M97.6 75.2l.5 .6M97.6 74.1l.5 .5M97.6 72.9l.5 .5M97.6 71.8l.5 .5M97.7 65.2l.5 .5M97.7 64l.5 .5M98.1 71.8l-.5 .5M98.1 72.9l-.5 .5M98.1 74.1l-.5 .5M98.1 75.2l-.5 .6M98.2 64l-.5 .5"/>
<path d="M98.2 65.2l-.5 .5M98.8 75.2l.5 .6M98.8 74.1l.5 .5M98.8 71.8l.5 .5M98.8 72.9l.5 .5M99.3 71.8l-.5 .5M99.3 72.9l-.5 .5M99.3 74.1l-.5 .5M99.3 75.2l-.5 .6M99.9 75.2l.6 .6M99.9 72.9l.6 .5M99.9 74.1l.6 .5"/>
<path d="M99.9 71.8l.6 .5M100.5 71.8l-.6 .5M100.5 72.9l-.6 .5M100.5 74.1l-.6 .5M100.5 75.2l-.6 .6M101.1 74.1l.5 .5M101.1 75.2l.5 .6M101.1 72.9l.5 .5M101.1 71.8l.5 .5M101.6 71.8l-.5 .5M101.6 72.9l-.5 .5M101.6 74.1l-.5 .5"/>
<path d="M101.6 75.2l-.5 .6M104.8 63.4l.5 .5M105.1 74.8l.5 .5M105.2 79.3l.5 .5M105.3 63.4l-.5 .5M105.6 74.8l-.5 .5M105.7 79.3l-.5 .5M105.8 72.4l.5 .5M106.3 72.4l-.5 .5M106.8 67.3l.5 .5M107.3 67.3l-.5 .5M108.1 78.5h1"/>
<path d="M108.6 77.9v1.1M109.5 64.3l.5 .5M110 64.3l-.5 .5M110.2 72l.6 .5M110.6 78.2l.5 .5M110.8 72l-.6 .5M111 73.8l.5 .5M111.1 78.2l-.5 .5M111.5 73.8l-.5 .5M112.2 74.4l.5 .5M112.3 62.2l.5 .5M112.7 74.4l-.5 .5"/>
<path d="M112.8 62.2l-.5 .5M113.5 70.3l.5 .6M114 70.3l-.5 .6M118.4 67.3l.5 .5M118.9 67.3l-.5 .5M119.4 73.7l.5 .5M119.9 73.7l-.5 .5M121.9 63l.5 .5M122.4 63l-.5 .5M122.7 73.8l1.3 1.4M122.7 74.5h1.3M122.8 67.9l.5 .5"/>
<path d="M123.3 67.9l-.5 .5M123.3 73.8v1.4M123.7 61.1l.5 .5M124 73.8l-1.3 1.4M124.2 61.1l-.5 .5M124.4 67.9l.5 .5M124.9 67.9l-.5 .5M125 64.7l.5 .5M125.5 64.7l-.5 .5M125.9 62.9l.5 .6M125.9 66l.5 .5M126.1 79.2l.5 .5"/>
<path d="M126.4 62.9l-.5 .6M126.4 66l-.5 .5M126.6 79.2l-.5 .5M127.3 67.1l.5 .5M127.8 65.9l.5 .5M127.8 67.1l-.5 .5M128.3 65.9l-.5 .5M129 68l.6 .5M129.6 68l-.6 .5M130 69.2l.5 .5M130.2 75.6l.5 .5M130.5 69.2l-.5 .5"/>
<path d="M130.7 75.6l-.5 .5M131.3 61.8l.5 .5M131.4 74.1l.5 .5M131.8 61.8l-.5 .5M131.8 69.5l.5 .5M131.9 74.1l-.5 .5M131.9 78.8l.6 .5M132.3 69.5l-.5 .5M132.5 78.8l-.6 .5M133.5 62.9l.5 .6M134 62.9l-.5 .6M134 65.1l.5 .5"/>
<path d="M134.2 66.3l.5 .6M134.2 80l.5 .5M134.3 69.5l.5 .5M134.4 73.7l.5 .5M134.4 76.9l.5 .5M134.5 65.1l-.5 .5M134.6 67.6l.5 .5M134.7 66.3l-.5 .6M134.7 80l-.5 .5M134.8 69.5l-.5 .5M134.9 73.7l-.5 .5M134.9 76.9l-.5 .5"/>
<path d="M135.1 67.6l-.5 .5M135.3 74.6l.5 .5M135.7 77.1l.5 .5M135.8 74.6l-.5 .5M135.9 69.5l.5 .5M136.2 77.1l-.5 .5M136.4 69.5l-.5 .5M136.6 76.1l.5 .6M137.1 76.1l-.5 .6M137.2 69.2l.5 .6M137.7 69.2l-.5 .6M138.9 75.2l.5 .6"/>
<path d="M139.4 75.2l-.5 .6M142 65.2l.5 .5M142.2 76.7l.5 .5M142.4 63l.5 .5M142.5 65.2l-.5 .5M142.7 76.7l-.5 .5M142.9 63l-.5 .5M143.1 74.2l.6 .5M143.7 74.2l-.6 .5M144.3 64.7l.5 .5M144.6 77.8l.5 .5M144.6 76.3l.6 .5"/>
<path d="M144.8 64.7l-.5 .5M145.1 77.8l-.5 .5M145.2 76.3l-.6 .5M145.2 69.8l.5 .5M145.7 61.8l.5 .5M145.7 69.8l-.5 .5M146.2 61.8l-.5 .5M146.5 69.7l.5 .5M147 69.7l-.5 .5M147.8 69.4l.5 .5M148.3 69.4l-.5 .5M148.9 64.2l.5 .5"/>
<path d="M149 69.7l.5 .5M149.4 64.2l-.5 .5M149.5 69.7l-.5 .5M153.2 77.9l.5 .6M153.2 80l.5 .5M153.7 77.9l-.5 .6M153.7 80l-.5 .5M154 64.2l.5 .5M154 78.9l.5 .5M154 69.8l.6 .5M154.2 72.1l.5 .6M154.4 74.5h1.4"/>
<path d="M154.4 73.8l1.4 1.4M154.5 64.2l-.5 .5M154.5 78.9l-.5 .5M154.6 69.8l-.6 .5M154.7 72.1l-.5 .6M155.1 60.3l.5 .5M155.1 73.8v1.4M155.6 60.3l-.5 .5M155.8 73.8l-1.4 1.4M157.1 79.9l.5 .5M157.6 79.9l-.5 .5M158.9 72.5l.6 .5"/>
<path d="M159.5 79.4l.5 .5M159.5 72.5l-.6 .5M160 79.4l-.5 .5M160.5 75.7l.6 .5M160.5 74.4l.6 .5M161.1 75.7l-.6 .5M161.1 74.4l-.6 .5M161.9 63.9l.5 .5M162.4 63.9l-.5 .5M163.6 70.9l.5 .5M164.1 70.9l-.5 .5M164.2 68.3l.5 .5"/>
<path d="M164.3 72.1l.6 .5M164.6 78.3l.5 .5M164.7 68.3l-.5 .5M164.9 72.1l-.6 .5M165.1 78.3l-.5 .5M165.4 75.1l.5 .5M165.9 75.1l-.5 .5M166 73.9l.5 .5M166.2 69.2l.5 .5M166.5 73.9l-.5 .5M166.7 69.2l-.5 .5M169 75.1l.5 .5"/>
<path d="M169.5 75.1l-.5 .5M170.4 60.2l.5 .5M170.8 76.2l.5 .5M170.9 60.2l-.5 .5M171.3 76.2l-.5 .5M172.4 73l.5 .5M172.8 70.2l.5 .6M172.8 75.3l1.3 1.3M172.9 73l-.5 .5M173.3 70.2l-.5 .6M174.1 75.3l-1.3 1.3M174.9 78.8l.5 .5"/>
<path d="M175.4 78.8l-.5 .5M175.6 70.3l.5 .6M176.1 70.3l-.5 .6M176.8 69.4l.5 .5M177.1 73.7l.5 .5M177.3 69.4l-.5 .5M177.4 63.3l.5 .5M177.6 73.7l-.5 .5M177.9 63.3l-.5 .5M178.4 61.5l.5 .5M178.8 68.4l.5 .5M178.9 61.5l-.5 .5"/>
<path d="M179.3 68.4l-.5 .5M179.3 75.3l1.3 1.3M179.9 65.9l.6 .5M180.5 65.9l-.6 .5M180.6 75.3l-1.3 1.3M183.9 62l.5 .5M184.3 74.5l.5 .5M184.4 62l-.5 .5M184.8 74.5l-.5 .5M185.7 63.5l.5 .5M186.2 63.5l-.5 .5M186.2 60.3l.6 .5"/>
<path d="M186.2 79.7l.6 .6M186.8 60.3l-.6 .5M186.8 79.7l-.6 .6M188.7 77h1M189.2 76.5v1M189.6 71l.5 .5M190.1 71l-.5 .5M191.7 77l.5 .6M191.9 75.8l.5 .5M191.9 74.5l.6 .5M192.2 77l-.5 .6M192.4 75.8l-.5 .5"/>
<path d="M192.5 74.5l-.6 .5M195.3 64.2l.5 .5M195.3 63l.5 .5M195.3 65.3l.5 .5M195.3 66.5l.5 .5M195.8 66.5l-.5 .5M195.8 65.3l-.5 .5M195.8 63l-.5 .5M195.8 64.2l-.5 .5M196.4 65.3l.5 .5M196.4 64.2l.5 .5M196.4 66.5l.5 .5"/>
<path d="M196.4 63l.5 .5M196.9 65.3l-.5 .5M196.9 64.2l-.5 .5M196.9 63l-.5 .5M196.9 66.5l-.5 .5M197.6 66.5l.5 .5M197.6 64.2l.5 .5M197.6 63l.5 .5M197.6 65.3l.5 .5M198.1 66.5l-.5 .5M198.1 64.2l-.5 .5M198.1 63l-.5 .5"/>
<path d="M198.1 65.3l-.5 .5M198.6 73.1l.5 .5M198.6 74.2l.5 .5M198.7 65.3l.6 .5M198.7 64.2l.6 .5M198.7 66.5l.6 .5M198.7 63l.6 .5M199.1 73.1l-.5 .5M199.1 74.2l-.5 .5M199.3 65.3l-.6 .5M199.3 63l-.6 .5M199.3 64.2l-.6 .5"/>
<path d="M199.3 66.5l-.6 .5M199.6 79.9l.5 .6M199.8 73.1l.5 .5M199.8 74.2l.5 .5M199.8 70.7l.5 .5M199.8 71.9l.5 .5M199.9 66.5l.5 .5M199.9 65.3l.5 .5M199.9 64.2l.5 .5M199.9 63l.5 .5M200.1 79.9l-.5 .6M200.3 71.9l-.5 .5"/>
<path d="M200.3 73.1l-.5 .5M200.3 70.7l-.5 .5M200.3 74.2l-.5 .5M200.4 64.2l-.5 .5M200.4 66.5l-.5 .5M200.4 63l-.5 .5M200.4 65.3l-.5 .5M200.9 74.2l.5 .5M200.9 71.9l.5 .5M200.9 73.1l.5 .5M200.9 70.7l.5 .5M201.1 66.5l.5 .5"/>
<path d="M201.1 65.3l.5 .5M201.1 64.2l.5 .5M201.1 63l.5 .5M201.4 74.2l-.5 .5M201.4 70.7l-.5 .5M201.4 71.9l-.5 .5M201.4 73.1l-.5 .5M201.6 63l-.5 .5M201.6 65.3l-.5 .5M201.6 64.2l-.5 .5M201.6 66.5l-.5 .5M202.1 73.1l.5 .5"/>
<path d="M202.1 71.9l.5 .5M202.1 70.7l.5 .5M202.2 66.5l.5 .5M202.2 65.3l.5 .5M202.2 64.2l.5 .5M202.2 63l.5 .5M202.6 70.7l-.5 .5M202.6 71.9l-.5 .5M202.6 73.1l-.5 .5M202.7 66.5l-.5 .5M202.7 64.2l-.5 .5M202.7 63l-.5 .5"/>
<path d="M202.7 65.3l-.5 .5M202.7 69.4h1.1M203.3 68.9v1.1M203.4 66.5l.5 .5M203.4 65.3l.5 .5M203.4 64.2l.5 .5M203.4 63l.5 .5M203.9 65.3l-.5 .5M203.9 63l-.5 .5M203.9 64.2l-.5 .5M203.9 66.5l-.5 .5M204.5 66.5l.6 .5"/>
<path d="M204.5 65.3l.6 .5M204.5 64.2l.6 .5M204.5 63l.6 .5M205.1 64.2l-.6 .5M205.1 63l-.6 .5M205.1 65.3l-.6 .5M205.1 66.5l-.6 .5M205.7 66.5l.5 .5M205.7 65.3l.5 .5M205.7 64.2l.5 .5M205.7 63l.5 .5M206.2 66.5l-.5 .5"/>
<path d="M206.2 63l-.5 .5M206.2 64.2l-.5 .5M206.2 65.3l-.5 .5M207.2 69.4h1.1M207.8 68.9v1.1M210.1 62.7l.5 .6M210.1 64l.5 .5M210.6 64l-.5 .5M210.6 62.7l-.5 .6M211.4 64l.5 .5M211.4 65.3l.5 .5M211.4 62.7l.5 .6"/>
<path d="M211.4 66.6l.5 .5M211.9 62.7l-.5 .6M211.9 64l-.5 .5M211.9 65.3l-.5 .5M211.9 66.6l-.5 .5M212.7 65.3l.5 .5M212.7 66.6l.5 .5M212.7 64l.5 .5M212.7 67.9l.5 .5M212.7 62.7l.5 .6M213.2 62.7l-.5 .6M213.2 67.9l-.5 .5"/>
<path d="M213.2 64l-.5 .5M213.2 65.3l-.5 .5M213.2 66.6l-.5 .5M213.9 66.6l.6 .5M213.9 67.9l.6 .5M213.9 65.3l.6 .5M213.9 62.7l.6 .6M213.9 64l.6 .5M214.3 69.4h1.1M214.5 66.6l-.6 .5M214.5 62.7l-.6 .6M214.5 64l-.6 .5"/>
<path d="M214.5 65.3l-.6 .5M214.5 67.9l-.6 .5M214.8 68.9v1.1M215.2 62.7l.5 .6M215.2 67.9l.5 .5M215.2 66.6l.5 .5M215.2 64l.5 .5M215.2 65.3l.5 .5M215.7 65.3l-.5 .5M215.7 62.7l-.5 .6M215.7 64l-.5 .5M215.7 66.6l-.5 .5"/>
<path d="M215.7 67.9l-.5 .5M218.8 69.4h1.1M219.4 68.9v1.1M74.6 90.5h.8v.8h-.8zM77.8 80.8h.9v.8h-.9zM88 81.2l.5 .5M88.5 81.2l-.5 .5M94.1 97.7l.5 .5M94.1 98.8l.5 .5M94.1 100l.5 .5M94.6 98.8l-.5 .5M94.6 97.7l-.5 .5"/>
<path d="M94.6 100l-.5 .5M95.2 98.8l.5 .5M95.2 100l.5 .5M95.2 97.7l.5 .5M95.7 97.7l-.5 .5M95.7 98.8l-.5 .5M95.7 100l-.5 .5M95.8 92.8l.5 .5M95.9 94l.5 .6M96.3 92.8l-.5 .5M96.4 100l.5 .5M96.4 98.8l.5 .5"/>
<path d="M96.4 94l-.5 .6M96.4 97.7l.5 .5M96.9 97.7l-.5 .5M96.9 98.8l-.5 .5M96.9 100l-.5 .5M97.6 97.7l.5 .5M97.6 98.8l.5 .5M98.1 97.7l-.5 .5M98.1 98.8l-.5 .5M103.7 83.3l.5 .5M104.2 83.3l-.5 .5M104.6 86.4l.5 .6"/>
<path d="M104.8 80.6l.5 .5M104.9 81.8l.5 .6M105.1 86.4l-.5 .6M105.2 94l.5 .6M105.2 96.1l.5 .5M105.3 80.6l-.5 .5M105.4 81.8l-.5 .6M105.7 94l-.5 .6M105.7 96.1l-.5 .5M108.1 90.4l.5 .6M108.1 83h1M108.6 90.4l-.5 .6"/>
<path d="M108.6 82.5v1M109 96.2l.5 .6M109.1 87.2l.6 .5M109.3 93.1l.6 .5M109.5 96.2l-.5 .6M109.5 85.4l.5 .5M109.7 87.2l-.6 .5M109.9 93.1l-.6 .5M110 85.4l-.5 .5M111.5 96.5l.5 .5M111.9 80.2l.5 .5M111.9 83.9l.5 .6"/>
<path d="M112 96.5l-.5 .5M112.4 80.2l-.5 .5M112.4 83.9l-.5 .6M113.1 92.7l.6 .5M113.7 92.7l-.6 .5M113.8 89.8l.5 .5M114.3 89.8l-.5 .5M116.5 83.4l.5 .5M116.9 97.9l.6 .5M117 83.4l-.5 .5M117.5 97.9l-.6 .5M118.1 99.2l.5 .5"/>
<path d="M118.6 99.2l-.5 .5M119.6 80.5l.5 .5M119.6 83l.5 .5M120.1 83l-.5 .5M120.1 80.5l-.5 .5M121.5 83l.5 .5M122 83l-.5 .5M124.3 87l.6 .5M124.4 80.1l.5 .6M124.9 87l-.6 .5M124.9 80.1l-.5 .6M125.1 83.9l.9-.9 .9 .9-.9 .9z"/>
<path d="M125.1 83l1.8 1.8M126.9 83l-1.8 1.8M128.3 93.3l.5 .6M128.8 93.3l-.5 .6M129.8 99.7l.5 .6M129.9 94l.5 .5M129.9 95.9l.5 .5M130.2 91.4l.5 .5M130.3 99.7l-.5 .6M130.4 94l-.5 .5M130.4 95.9l-.5 .5M130.5 80.3l.5 .5"/>
<path d="M130.7 91.4l-.5 .5M131 80.3l-.5 .5M131 98.8l.5 .5M131.5 98.8l-.5 .5M131.5 91.4l.5 .5M132 91.4l-.5 .5M132.7 96.9l.5 .6M133.2 96.9l-.5 .6M133.4 82.4l.5 .5M133.6 97.9l.5 .5M133.9 82.4l-.5 .5M134.1 97.9l-.5 .5"/>
<path d="M134.4 81.1l.5 .5M134.9 81.1l-.5 .5M135 95.9l.5 .5M135.4 82.3l.5 .5M135.5 95.9l-.5 .5M135.9 82.3l-.5 .5M136.4 98.5l.5 .5M136.6 81.4l.6 .5M136.9 98.5l-.5 .5M137.2 81.4l-.6 .5M138.2 95.1l.5 .6M138.4 86.6l.6 .5"/>
<path d="M138.6 84.1l.5 .5M138.7 95.1l-.5 .6M138.9 85.3l.5 .5M139 86.6l-.6 .5M139.1 94l.5 .6M139.1 88.8l.5 .5M139.1 84.1l-.5 .5M139.2 92.2l.5 .5M139.4 85.3l-.5 .5M139.6 94l-.5 .6M139.6 88.8l-.5 .5M139.7 92.2l-.5 .5"/>
<path d="M139.9 87l.5 .5M140.3 89.1l.5 .6M140.4 87l-.5 .5M140.8 89.1l-.5 .6M141.7 91.2l.5 .5M142.2 91.2l-.5 .5M142.3 99.1l.5 .5M142.6 80.4l.6 .5M142.8 99.1l-.5 .5M143 94.6l.5 .5M143.2 80.4l-.6 .5M143.5 94.6l-.5 .5"/>
<path d="M143.9 88.7l.5 .5M144.2 89.9l.6 .5M144.4 88.7l-.5 .5M144.7 80.5l.5 .5M144.8 89.9l-.6 .5M144.8 91.4l.5 .5M145.2 80.5l-.5 .5M145.3 91.4l-.5 .5M145.8 89l.5 .5M146.3 89l-.5 .5M147.3 95.1l.5 .5M147.8 95.1l-.5 .5"/>
<path d="M147.8 91.1l.5 .5M148.3 91.1l-.5 .5M148.4 90l.5 .5M148.9 90l-.5 .5M149 92.1l.5 .5M149.5 92.1l-.5 .5M150.6 97.4l.5 .5M151.1 97.4l-.5 .5M153.2 88.2l.5 .5M153.4 81.9l.5 .6M153.7 88.2l-.5 .5M153.9 81.9l-.5 .6"/>
<path d="M154 89.3l.5 .5M154.1 80.9l.5 .5M154.5 89.3l-.5 .5M154.6 80.9l-.5 .5M155 92.2l.5 .5M155.5 92.2l-.5 .5M156 87.9l.5 .5M156.3 82.2l.5 .5M156.5 87.9l-.5 .5M156.6 98.5l.5 .5M156.8 82.2l-.5 .5M157 81.1l.5 .6"/>
<path d="M157 93.7l.5 .5M157.1 98.5l-.5 .5M157.5 81.1l-.5 .6M157.5 93.7l-.5 .5M157.8 85.3l.5 .5M157.8 89.1l.5 .5M158.3 85.3l-.5 .5M158.3 89.1l-.5 .5M159.9 87.9l1.3 1.3M159.9 91.2l1.3 1.3M159.9 84.6l1.3 1.3M159.9 94.4l1.3 1.3"/>
<path d="M161.2 87.9l-1.3 1.3M161.2 94.4l-1.3 1.3M161.2 84.6l-1.3 1.3M161.2 91.2l-1.3 1.3M161.6 98.2l.5 .5M162.1 98.2l-.5 .5M163.9 80.1l.5 .5M164.2 82.3l.5 .5M164.4 80.1l-.5 .5M164.7 82.3l-.5 .5M164.9 98.3l.5 .5M165 80.7l.5 .5"/>
<path d="M165.4 98.3l-.5 .5M165.5 80.7l-.5 .5M166 84.9l.5 .5M166 86.6l.5 .5M166.5 84.9l-.5 .5M166.5 86.6l-.5 .5M167.1 93.5l.5 .5M167.1 82.5l.5 .5M167.6 93.5l-.5 .5M167.6 82.5l-.5 .5M167.8 89.2l.5 .5M168 98.7l.5 .5"/>
<path d="M168.1 85.8l.5 .6M168.3 89.2l-.5 .5M168.5 98.7l-.5 .5M168.6 85.8l-.5 .6M170.5 90.8l.5 .5M171 90.8l-.5 .5M173.8 81.3l.5 .5M174.3 81.3l-.5 .5M175.7 89.3l.5 .5M175.7 99.7l.5 .5M175.8 85.9l.5 .5M175.8 83.7l.5 .6"/>
<path d="M176.2 99.7l-.5 .5M176.2 89.3l-.5 .5M176.3 83.7l-.5 .6M176.3 85.9l-.5 .5M178.5 94l.7-.6 .6 .6-.6 .7zM178.5 97.3l.7-.6 .6 .6-.6 .6zM179.2 87l.6 .6-.6 .6-.7-.6zM179.2 90.2l.6 .6-.6 .6-.7-.6zM181.4 85.3l.5 .5M181.9 85.3l-.5 .5M182 89l.5 .5M182.5 89l-.5 .5"/>
<path d="M182.6 92l.6 .5M183.2 92l-.6 .5M183.5 97l.6 .5M184.1 97l-.6 .5M184.2 85.3l.5 .5M184.4 88.9l.6 .5M184.7 85.3l-.5 .5M185 88.9l-.6 .5M186.4 94l.6-.6 .6 .6-.6 .7zM186.4 97.3l.6-.6 .6 .6-.6 .6zM187 87l.6 .6-.6 .6-.6-.6zM187 90.2l.6 .6-.6 .6-.6-.6z"/>
<path d="M188.7 81.5h1M189.2 81v1M192.3 83.8l.5 .5M192.8 83.8l-.5 .5M195.3 99.8l.5 .6M195.3 96.4l.5 .5M195.3 97.5l.5 .5M195.3 98.7l.5 .5M195.8 96.4l-.5 .5M195.8 97.5l-.5 .5M195.8 98.7l-.5 .5M195.8 99.8l-.5 .6"/>
<path d="M196.4 97.5l.5 .5M196.4 98.7l.5 .5M196.4 99.8l.5 .6M196.4 96.4l.5 .5M196.9 96.4l-.5 .5M196.9 97.5l-.5 .5M196.9 98.7l-.5 .5M196.9 99.8l-.5 .6M197.6 98.7l.5 .5M197.6 99.8l.5 .6M197.6 96.4l.5 .5M197.6 97.5l.5 .5"/>
<path d="M198.1 96.4l-.5 .5M198.1 97.5l-.5 .5M198.1 98.7l-.5 .5M198.1 99.8l-.5 .6M198.3 80l.5 .5M198.7 99.8l.6 .6M198.7 97.5l.6 .5M198.7 98.7l.6 .5M198.7 96.4l.6 .5M198.8 80l-.5 .5M199.3 96.4l-.6 .5M199.3 97.5l-.6 .5"/>
<path d="M199.3 98.7l-.6 .5M199.3 99.8l-.6 .6M199.9 98.7l.5 .5M199.9 99.8l.5 .6M199.9 97.5l.5 .5M199.9 96.4l.5 .5M200.4 96.4l-.5 .5M200.4 97.5l-.5 .5M200.4 98.7l-.5 .5M200.4 99.8l-.5 .6M201.1 99.8l.5 .6M201.1 98.7l.5 .5"/>
<path d="M201.1 97.5l.5 .5M201.1 96.4l.5 .5M201.6 96.4l-.5 .5M201.6 97.5l-.5 .5M201.6 98.7l-.5 .5M201.6 99.8l-.5 .6M202.2 99.8l.5 .6M202.2 98.7l.5 .5M202.2 97.5l.5 .5M202.2 96.4l.5 .5M202.7 96.4l-.5 .5M202.7 97.5l-.5 .5"/>
<path d="M202.7 98.7l-.5 .5M202.7 99.8l-.5 .6M203.4 99.8l.5 .6M203.4 98.7l.5 .5M203.4 97.5l.5 .5M203.4 96.4l.5 .5M203.9 96.4l-.5 .5M203.9 97.5l-.5 .5M203.9 98.7l-.5 .5M203.9 99.8l-.5 .6M204.5 99.8l.6 .6M204.5 98.7l.6 .5"/>
<path d="M204.5 97.5l.6 .5M204.5 96.4l.6 .5M205.1 96.4l-.6 .5M205.1 97.5l-.6 .5M205.1 98.7l-.6 .5M205.1 99.8l-.6 .6M205.7 96.4l.5 .5M205.7 99.8l.5 .6M205.7 98.7l.5 .5M205.7 97.5l.5 .5M206.2 96.4l-.5 .5M206.2 97.5l-.5 .5"/>
<path d="M206.2 98.7l-.5 .5M206.2 99.8l-.5 .6M208.8 87.9l.5 .5M209.3 87.9l-.5 .5M210.1 96.2l.5 .6M210.1 97.5l.5 .5M210.6 96.2l-.5 .6M210.6 97.5l-.5 .5M211.4 97.5l.5 .5M211.4 98.8l.5 .5M211.4 96.2l.5 .6M211.9 96.2l-.5 .6"/>
<path d="M211.9 97.5l-.5 .5M211.9 98.8l-.5 .5M212.7 98.8l.5 .5M212.7 97.5l.5 .5M212.7 96.2l.5 .6M213.2 97.5l-.5 .5M213.2 98.8l-.5 .5M213.2 96.2l-.5 .6M213.9 98.8l.6 .5M213.9 97.5l.6 .5M213.9 96.2l.6 .6M214.5 96.2l-.6 .6"/>
<path d="M214.5 97.5l-.6 .5M214.5 98.8l-.6 .5M215.2 98.8l.5 .5M215.2 96.2l.5 .6M215.2 97.5l.5 .5M215.7 96.2l-.5 .6M215.7 97.5l-.5 .5M215.7 98.8l-.5 .5M218.9 90.5h.8v.8h-.8zM222.1 80.8h.9v.8h-.9zM77.1 102.9h1.1M77.6 102.4v1.1"/>
<path d="M81.3 104l.5 .5M81.3 105.3l.5 .5M81.3 106.5l.5 .6M81.3 107.8l.5 .5M81.3 109.1l.5 .5M81.6 102.9h1.1M81.8 104l-.5 .5M81.8 105.3l-.5 .5M81.8 106.5l-.5 .6M81.8 107.8l-.5 .5M81.8 109.1l-.5 .5M82.2 102.4v1.1"/>
<path d="M82.5 105.3l.6 .5M82.5 107.8l.6 .5M82.5 109.1l.6 .5M82.5 104l.6 .5M82.5 106.5l.6 .6M83.1 104l-.6 .5M83.1 105.3l-.6 .5M83.1 106.5l-.6 .6M83.1 107.8l-.6 .5M83.1 109.1l-.6 .5M83.8 106.5l.5 .6M83.8 109.1l.5 .5"/>
<path d="M83.8 105.3l.5 .5M83.8 107.8l.5 .5M83.8 104l.5 .5M84.3 104l-.5 .5M84.3 105.3l-.5 .5M84.3 106.5l-.5 .6M84.3 107.8l-.5 .5M84.3 109.1l-.5 .5M85.1 107.8l.5 .5M85.1 106.5l.5 .6M85.1 109.1l.5 .5M85.1 105.3l.5 .5"/>
<path d="M85.6 105.3l-.5 .5M85.6 106.5l-.5 .6M85.6 107.8l-.5 .5M85.6 109.1l-.5 .5M86.4 109.1l.5 .5M86.4 107.8l.5 .5M86.9 107.8l-.5 .5M86.9 109.1l-.5 .5M87.7 114.9l.5 .5M88.2 114.9l-.5 .5M88.7 102.9h1.1M89.2 102.4v1.1"/>
<path d="M90.7 105.3l.5 .5M90.7 106.4l.5 .5M90.7 107.6l.5 .5M90.7 108.7l.5 .5M91.2 105.3l-.5 .5M91.2 106.4l-.5 .5M91.2 107.6l-.5 .5M91.2 108.7l-.5 .5M91.8 106.4l.5 .5M91.8 107.6l.5 .5M91.8 108.7l.5 .5M91.8 105.3l.5 .5"/>
<path d="M92.3 105.3l-.5 .5M92.3 106.4l-.5 .5M92.3 107.6l-.5 .5M92.3 108.7l-.5 .5M93 107.6l.5 .5M93 108.7l.5 .5M93 106.4l.5 .5M93 105.3l.5 .5M93.2 102.9h1.1M93.5 105.3l-.5 .5M93.5 106.4l-.5 .5M93.5 107.6l-.5 .5"/>
<path d="M93.5 108.7l-.5 .5M93.8 102.4v1.1M94.1 101.1l.5 .5M94.1 108.7l.6 .5M94.1 107.6l.6 .5M94.1 106.4l.6 .5M94.1 105.3l.6 .5M94.6 101.1l-.5 .5M94.7 105.3l-.6 .5M94.7 106.4l-.6 .5M94.7 107.6l-.6 .5M94.7 108.7l-.6 .5"/>
<path d="M95.2 101.1l.5 .5M95.3 108.7l.5 .5M95.3 107.6l.5 .5M95.3 106.4l.5 .5M95.3 105.3l.5 .5M95.7 101.1l-.5 .5M95.8 105.3l-.5 .5M95.8 106.4l-.5 .5M95.8 107.6l-.5 .5M95.8 108.7l-.5 .5M96.4 101.1l.5 .5M96.5 107.6l.5 .5"/>
<path d="M96.5 106.4l.5 .5M96.5 105.3l.5 .5M96.5 108.7l.5 .5M96.9 101.1l-.5 .5M97 105.3l-.5 .5M97 106.4l-.5 .5M97 107.6l-.5 .5M97 108.7l-.5 .5M97.6 108.7l.5 .5M97.6 107.6l.5 .5M97.6 106.4l.5 .5M97.6 105.3l.5 .5"/>
<path d="M98.1 105.3l-.5 .5M98.1 106.4l-.5 .5M98.1 107.6l-.5 .5M98.1 108.7l-.5 .5M98.8 108.7l.5 .5M98.8 107.6l.5 .5M98.8 106.4l.5 .5M98.8 105.3l.5 .5M99.3 105.3l-.5 .5M99.3 106.4l-.5 .5M99.3 107.6l-.5 .5M99.3 108.7l-.5 .5"/>
<path d="M99.9 108.7l.6 .5M99.9 107.6l.6 .5M99.9 106.4l.6 .5M99.9 105.3l.6 .5M100.5 105.3l-.6 .5M100.5 106.4l-.6 .5M100.5 107.6l-.6 .5M100.5 108.7l-.6 .5M101.1 108.7l.5 .5M101.1 107.6l.5 .5M101.1 106.4l.5 .5M101.1 105.3l.5 .5"/>
<path d="M101.6 105.3l-.5 .5M101.6 106.4l-.5 .5M101.6 107.6l-.5 .5M101.6 108.7l-.5 .5M104.1 113.2h1M104.1 117.7h1M104.6 112.7v1M104.6 117.2v1M107 100.1l.5 .5M107.5 100.1l-.5 .5M108.1 115.3l.5 .5M108.6 115.3l-.5 .5"/>
<path d="M109.6 118.5l.5 .5M110.1 118.5l-.5 .5M110.8 109.4l.5 .5M110.9 114.3l.6 .5M111.3 109.4l-.5 .5M111.5 114.3l-.6 .5M113.4 118.4l.6-.6 .6 .6-.6 .6zM113.7 111.3l.5 .5M114 114.4l.5 .5M114.2 111.3l-.5 .5M114.5 114.4l-.5 .5M114.7 104.9l.6 .5"/>
<path d="M115.3 104.9l-.6 .5M115.7 109.5l.5 .5M116.2 109.5l-.5 .5M116.6 118.4l.6-.6 .6 .6-.6 .6zM117.6 105.5l1.3 1.3M118.9 105.5l-1.3 1.3M119.4 102.9l.5 .6M119.8 118.4l.6-.6 .6 .6-.6 .6zM119.9 102.9l-.5 .6M123 118.4l.6-.6 .7 .6-.7 .6zM123.9 104.6l.5 .5M124 107.6l.5 .5"/>
<path d="M124.4 104.6l-.5 .5M124.5 107.6l-.5 .5M126 105.5l1.3 1.3M126.6 117.8l.5 .5M127 109.8l.5 .6M127.1 117.8l-.5 .5M127.3 105.5l-1.3 1.3M127.5 109.8l-.5 .6M127.8 112l.5 .5M127.8 119.1l.5 .5M128.3 112l-.5 .5M128.3 119.1l-.5 .5"/>
<path d="M129.2 112.3l.5 .6M129.4 108.6l.6 .5M129.7 112.3l-.5 .6M129.9 118.4l.6-.6 .6 .6-.6 .6zM130 108.6l-.6 .5M131.1 100.7l.5 .5M131.6 100.7l-.5 .5M131.8 116.1l.5 .6M132.3 116.1l-.5 .6M132.9 105.6l.5 .5M133.1 118.4l.6-.6 .6 .6-.6 .6zM133.4 105.6l-.5 .5"/>
<path d="M134.7 116.1l.5 .6M135.1 105.8l.5 .5M135.1 102.4l.5 .5M135.2 116.1l-.5 .6M135.6 105.8l-.5 .5M135.6 102.4l-.5 .5M136.3 118.4l.6-.6 .6 .6-.6 .6zM136.4 103.6l.6 .5M137 103.6l-.6 .5M137.3 101.1l.5 .5M137.8 101.1l-.5 .5M138 100l.5 .5"/>
<path d="M138.5 100l-.5 .5M139.5 118.4l.6-.6 .6 .6-.6 .6zM140.5 105.9l.5 .5M141 105.9l-.5 .5M141.2 102.1l.5 .5M141.7 102.1l-.5 .5M142.7 118.4l.6-.6 .7 .6-.7 .6zM143.2 102.3l.5 .5M143.5 115.7l.5 .5M143.7 102.3l-.5 .5M143.9 109.9l.5 .5M144 115.7l-.5 .5"/>
<path d="M144.2 100.4l.5 .5M144.4 109.9l-.5 .5M144.4 103.9l.5 .6M144.7 100.4l-.5 .5M144.9 103.9l-.5 .6M146.2 103.6l.5 .5M146.3 102.3l.5 .5M146.7 103.6l-.5 .5M146.8 102.3l-.5 .5M147.2 119.4l.5 .5M147.4 115.6l.5 .5M147.5 100.8l.5 .5"/>
<path d="M147.7 119.4l-.5 .5M147.9 117.5l.5 .5M147.9 115.6l-.5 .5M148 110.2l.5 .5M148 100.8l-.5 .5M148.4 117.5l-.5 .5M148.5 110.2l-.5 .5M148.5 119.4l.5 .5M148.6 115.6l.5 .5M149 119.4l-.5 .5M149.1 115.6l-.5 .5M149.5 102l.5 .5"/>
<path d="M150 102l-.5 .5M150.5 118.4l.6-.6 .6 .6-.6 .6zM151.3 112.5l.6 .5M151.3 106.4l.6 .5M151.9 106.4l-.6 .5M151.9 112.5l-.6 .5M151.9 103.2l.5 .5M152.4 103.2l-.5 .5M153.7 118.4l.6-.6 .6 .6-.6 .6zM154.7 101.3l.5 .5M155.2 101.3l-.5 .5M156.9 118.4l.6-.6 .6 .6-.6 .6z"/>
<path d="M158 106.1l.5 .5M158.4 116.2l.5 .5M158.5 106.1l-.5 .5M158.9 116.2l-.5 .5M160.1 118.4l.6-.6 .7 .6-.7 .6zM160.2 106l.5 .5M160.3 102.9l.5 .5M160.7 106l-.5 .5M160.8 102.9l-.5 .5M161.9 102.8l.5 .5M162.4 102.8l-.5 .5M163.3 118.4l.7-.6 .6 .6-.6 .6z"/>
<path d="M164.7 109.4l.5 .5M165.2 109.4l-.5 .5M166 110.2l.5 .5M166.5 110.2l-.5 .5M167.6 110.7l.5 .5M167.8 118.3l.5 .5M168.1 110.7l-.5 .5M168.3 118.3l-.5 .5M169 105.3l.5 .5M169.5 105.3l-.5 .5M169.7 102.5l.5 .5M170.2 102.5l-.5 .5"/>
<path d="M170.3 105.1l.5 .5M170.4 118.4l.6-.6 .7 .6-.7 .6zM170.8 105.1l-.5 .5M170.9 102.5l.5 .5M171.4 102.5l-.5 .5M172.3 102.6l.5 .5M172.3 105.1l.5 .5M172.8 102.6l-.5 .5M172.8 105.1l-.5 .5M173.7 118.4l.6-.6 .6 .6-.6 .6zM176.9 118.4l.6-.6 .6 .6-.6 .6zM177.4 105.6l.5 .5"/>
<path d="M177.9 105.6l-.5 .5M180.1 118.4l.6-.6 .6 .6-.6 .6zM182.9 106.2l.5 .5M182.9 100.1l.5 .5M183.4 100.1l-.5 .5M183.4 106.2l-.5 .5M184.2 108.3l.5 .6M184.4 112.6l.6 .5M184.6 115.7l.5 .5M184.7 108.3l-.5 .6M185 112.6l-.6 .5M185.1 115.7l-.5 .5"/>
<path d="M185.7 118l.5 .5M186.2 118l-.5 .5M187.9 112h1.1M187.9 116.5h1.1M188.4 111.4v1.1M188.4 115.9v1.1M189.5 104l.5 .5M190 104l-.5 .5M190.8 109l.5 .5M191.1 118.4l.6 .5M191.3 109l-.5 .5M191.7 118.4l-.6 .5"/>
<path d="M191.7 113.2l.5 .6M192.2 113.2l-.5 .6M198.4 113.1l.5 .5M198.6 106.5l.5 .6M198.6 107.7l.5 .5M198.9 113.1l-.5 .5M199.1 106.5l-.5 .6M199.1 107.7l-.5 .5M199.5 113l.5 .5M199.8 107.7l.5 .5M199.8 104.2l.5 .5M199.8 105.4l.5 .5"/>
<path d="M199.8 106.5l.5 .6M200 113l-.5 .5M200.3 105.4l-.5 .5M200.3 106.5l-.5 .6M200.3 104.2l-.5 .5M200.3 107.7l-.5 .5M200.9 105.4l.5 .5M200.9 106.5l.5 .6M200.9 104.2l.5 .5M201.4 104.2l-.5 .5M201.4 105.4l-.5 .5M201.4 106.5l-.5 .6"/>
<path d="M202.1 104.2l.5 .5M202.1 106.5l.5 .6M202.1 107.7l.5 .5M202.1 105.4l.5 .5M202.6 104.2l-.5 .5M202.6 105.4l-.5 .5M202.6 106.5l-.5 .6M202.6 107.7l-.5 .5M202.7 102.9h1.1M203.3 102.4v1.1M207.2 102.9h1.1M207.8 102.4v1.1"/>
<path d="M211.4 100.1l.5 .5M211.9 100.1l-.5 .5M212.7 100.1l.5 .5M212.7 101.4l.5 .5M213.2 100.1l-.5 .5M213.2 101.4l-.5 .5M213.9 100.1l.6 .5M213.9 101.4l.6 .5M214.3 102.9h1.1M214.5 100.1l-.6 .5M214.5 101.4l-.6 .5M214.8 102.4v1.1"/>
<path d="M215.2 101.4l.5 .5M215.2 100.1l.5 .5M215.7 100.1l-.5 .5M215.7 101.4l-.5 .5M218.8 102.9h1.1M219.4 102.4v1.1M69.9 140l1.3 1.2M70.1 132.7h1.1M70.2 134.9h.8v.8h-.8zM70.6 137.4l.6 .6-.6 .6-.6-.6zM70.7 127.1l.5 .6M70.7 132.2v1"/>
<path d="M71.2 127.1l-.5 .6M71.2 140l-1.3 1.2M79 122.1v1.7l.3 .3M85.3 127l.5 .1 .1 .2M85.3 129.6l.5 .1 .1 .2M85.3 132.3l.5 .1 .1 .2M85.3 134.9l.5 .1 .1 .2M85.3 137.5l.5 .1 .1 .2M85.9 127.3l.3-.3 .4 .1 .1 1.2M85.9 127.3v1M85.9 129.9v1.1M85.9 132.6v1"/>
<path d="M85.9 135.2v1M85.9 137.8v1.1M85.9 129.9l.3-.3 .4 .1 .1 1.3M85.9 132.6l.3-.3 .4 .1 .1 1.2M85.9 135.2l.3-.3 .4 .1 .1 1.2M85.9 137.8l.3-.3 .4 .1 .1 1.3M90.6 126.2l-1.7 2.6M90.6 128.9l-1.7 2.5M90.6 131.5l-1.7 2.6M90.6 134.1l-1.7 2.6M90.6 136.8l-1.7 2.6M90.6 139.4l-1.7 2.6"/>
<path d="M103.2 126.3v.4M103.2 129v.3M103.2 131.6v.4M103.2 134.2v.4M103.2 136.9v.4M103.2 139.5v.4M104 126.3v.4M104 129v.3M104 131.6v.4M104 134.2v.4M104 136.9v.4M104 139.5v.4"/>
<path d="M113.3 127.7h1.2M69.2 151.6h2M69.4 148.6l.9-.9 .9 .9-.9 .9zM69.4 147.7l1.8 1.8M69.5 154.1h1.4v1.4h-1.4zM69.6 145.1l1.6 1.6M69.8 142.6l1.4 1.3M69.8 143.2h1.4M69.9 145.3h1v1.1h-1zM70.2 157l1 1-1 1-1-1zM70.2 150.6v2M70.5 142.6v1.3"/>
<path d="M71.2 142.6l-1.4 1.3M71.2 145.1l-1.6 1.6M71.2 147.7l-1.8 1.8M85.3 140.2l.5 .1 .1 .2M85.3 142.8l.5 .1 .1 .2M85.3 145.5l.5 .1 .1 .2M85.3 148.2l.5 .1 .1 .2M85.3 151.2l.5 .1 .1 .2M85.3 154.4l.5 .1 .1 .2M85.3 157.6l.5 .1 .1 .2M85.9 140.5v1M85.9 143.1v1.1"/>
<path d="M85.9 145.8v1M85.9 148.5v1M85.9 151.5v1M85.9 154.7v1M85.9 157.9v1M85.9 140.5l.3-.3 .4 .1 .1 1.2M85.9 143.1l.3-.3 .4 .1 .1 1.3M85.9 145.8l.3-.3 .4 .1 .1 1.2M85.9 148.5l.3-.3 .4 .1 .1 1.2M85.9 151.5l.3-.3 .4 .1 .1 1.2M85.9 154.7l.3-.3 .4 .1 .1 1.2M85.9 157.9l.3-.3 .4 .1 .1 1.2"/>
<path d="M90.6 142.1l-1.7 2.5M90.6 144.7l-1.7 2.6M90.6 147.4l-1.7 2.6M90.6 150.5l-1.7 2.5M90.6 153.7l-1.7 2.5M90.6 156.9l-1.7 2.5M103.2 142.2v.3M103.2 144.8v.4M103.2 147.5v.4M103.2 150.5v.4M103.2 153.7v.4M103.2 156.9v.4"/>
<path d="M104 142.2v.3M104 144.8v.4M104 147.5v.4M104 150.5v.4M104 153.7v.4M104 156.9v.4"/>
<circle cx="72.5" cy="10.2" r=".39"/>
<circle cx="73.6" cy="7.5" r=".39"/>
<circle cx="76.4" cy="6.3" r=".39"/>
<circle cx="220.6" cy="6.3" r=".39"/>
<circle cx="223.4" cy="7.5" r=".39"/>
<circle cx="224.5" cy="10.2" r=".39"/>
<circle cx="107.3" cy="26.5" r=".64"/>
<circle cx="110.5" cy="26.5" r=".64"/>
<circle cx="172.6" cy="27.8" r=".64"/>
<circle cx="172.6" cy="34.3" r=".64"/>
<circle cx="164.2" cy="43.8" r=".64"/>
<circle cx="170.7" cy="43.8" r=".64"/>
<circle cx="173.5" cy="75.9" r=".64"/>
<circle cx="179.9" cy="75.9" r=".64"/>
<circle cx="160.5" cy="88.5" r=".64"/>
<circle cx="160.5" cy="95.1" r=".64"/>
<circle cx="160.5" cy="91.8" r=".64"/>
<circle cx="160.5" cy="85.3" r=".64"/>
<circle cx="72.5" cy="115.8" r=".39"/>
<circle cx="73.6" cy="118.6" r=".39"/>
<circle cx="76.4" cy="119.7" r=".39"/>
<circle cx="118.3" cy="106.2" r=".64"/>
<circle cx="126.7" cy="106.2" r=".64"/>
<circle cx="220.6" cy="119.7" r=".39"/>
<circle cx="223.4" cy="118.6" r=".39"/>
<circle cx="224.5" cy="115.8" r=".39"/>
<circle cx="70.8" cy="130" r=".39"/>
<circle cx="70.2" cy="158" r="1"/>
<circle cx="70.2" cy="151.6" r="1"/>
<circle cx="70.2" cy="154.8" r="1"/>
<circle cx="70.5" cy="140.6" r=".64"/>
</g>
<g fill="none" stroke="#000" stroke-width=".35">
<path d="M146.8 9.4h3.4M148.5 7.7v3.5"/>
<circle cx="148.5" cy="9.4" r="1.74"/>
</g>
<g fill="none" stroke="#000" stroke-width=".39">
<path d="M147.1 19.1h2.8v2.8h-2.8zM98.2 33.3h2.7v2.7h-2.7zM196.1 35.9h2.7v2.7h-2.7zM98.2 66.8h2.7v2.7h-2.7zM196.1 69.4h2.7v2.7h-2.7zM98.2 100.3h2.7v2.7h-2.7zM196.1 102.9h2.7v2.7h-2.7z"/>
<circle cx="99.5" cy="34.7" r="1.93"/>
<circle cx="148.5" cy="20.5" r="1.93"/>
<circle cx="197.5" cy="37.2" r="1.93"/>
<circle cx="99.5" cy="68.2" r="1.93"/>
<circle cx="197.5" cy="70.7" r="1.93"/>
<circle cx="99.5" cy="101.6" r="1.93"/>
<circle cx="197.5" cy="104.2" r="1.93"/>
</g>
<g fill="none" stroke="#000" stroke-width=".52">
<path d="M73.8 10.2l2.6-2.6 2.5 2.6-2.5 2.6zM218.1 10.2l2.5-2.6 2.6 2.6-2.6 2.6zM73.8 115.8l2.6-2.6 2.5 2.6-2.5 2.6zM220.6 113.2l2.6 2.6-2.6 2.6-2.5-2.6z"/>
<circle cx="76.4" cy="10.2" r="2.58"/>
<circle cx="220.6" cy="10.2" r="2.58"/>
<circle cx="76.4" cy="115.8" r="2.58"/>
<circle cx="220.6" cy="115.8" r="2.58"/>
</g>
<use href="#words"/>
</svg>
